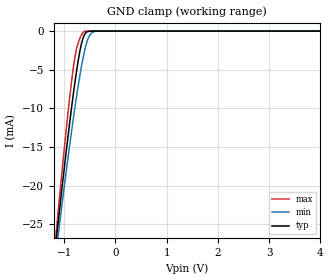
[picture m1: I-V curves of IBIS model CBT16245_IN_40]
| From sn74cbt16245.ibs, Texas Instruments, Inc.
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[Model]   CBT16245_IN_40
Model_type  Input
Vinl = 0.8
Vinh = 2.0
| variable   typ   min   max
C_comp   1.72pF   1.36pF   2.02pF
[Temperature Range]   40   100   -40
| Ambient temperature   25   85   -40
[Voltage range]   4   4   4
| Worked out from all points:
|   GND clamp passes 1 mA (typ) near -0.63 V on its own axis
[GND Clamp]
| CBT16245_IN_40
|   Voltage   I(typ)   I(min)   I(max)
-4V       -223.5mA   -205.4mA   -251.7mA
-1.17V    -28.09mA   -29.44mA   -27.18mA
-1.135V   -25.96mA   -27.52mA   -24.71mA
-1.105V   -24.15mA   -25.9mA    -22.62mA
-940mV    -14.56mA   -17.24mA   -11.62mA
-815mV    -7.933mA   -11.12mA   -4.547mA
-730mV    -4.048mA   -7.314mA   -1.648mA
-665mV    -1.753mA   -4.714mA   -540.1uA
-605mV    -503.4uA   -2.694mA   -38.13uA
-495mV    -19.7uA    -496.6uA   -183.5nA
-350mV    -218.9nA   -15.84uA   -566.2pA
4V        44.9pA     1.797nA    38.62pA
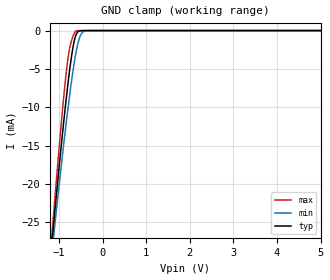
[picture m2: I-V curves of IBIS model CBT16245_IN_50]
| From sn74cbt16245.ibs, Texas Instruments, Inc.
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[Model]   CBT16245_IN_50
Model_type  Input
Vinl = 0.8
Vinh = 2.0
| variable   typ   min   max
C_comp   1.85pF   1.32pF   3.88pF
[Temperature Range]   40   100   -40
| Ambient temperature   25   85   -40
[Voltage range]   5   4.5   5.5
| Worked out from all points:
|   GND clamp passes 1 mA (typ) near -0.63 V on its own axis
[GND Clamp]
| CBT16245_IN_50
|   Voltage   I(typ)   I(min)   I(max)
-5V       -295.8mA   -271mA     -334.4mA
-1.165V   -27.79mA   -29.16mA   -26.83mA
-1.125V   -25.35mA   -26.98mA   -24.01mA
-1.09V    -23.25mA   -25.09mA   -21.58mA
-915mV    -13.17mA   -15.97mA   -10.07mA
-815mV    -7.933mA   -11.12mA   -4.547mA
-725mV    -3.845mA   -7.103mA   -1.541mA
-665mV    -1.753mA   -4.714mA   -540.1uA
-605mV    -503.4uA   -2.694mA   -38.13uA
-490mV    -16.91uA   -448.5uA   -150.3nA
-340mV    -160.5nA   -12.22uA   -381.2pA
5V        55.96pA    1.819nA    44.39pA
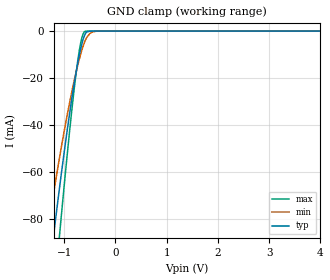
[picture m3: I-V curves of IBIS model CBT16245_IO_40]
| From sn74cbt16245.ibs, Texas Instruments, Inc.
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[Model]   CBT16245_IO_40
Model_type  Terminator
| variable   typ   min   max
C_comp   2.88pF   2.34pF   3.59pF
| C_tri-state   2.88pF   2.34pF   3.59pF
[Temperature Range]   40   100   -40
| Ambient temperature   25   85   -40
[Voltage range]   4   4   4
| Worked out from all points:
|   GND clamp passes 1 mA (typ) near -0.58 V on its own axis
[GND Clamp]
| CBT16245_IO_40
|   Voltage   I(typ)   I(min)   I(max)
-4V       -1.707A    -1.716A    -1.581A
-1.315V   -107.5mA   -84.68mA   -142.9mA
-1.18V    -82.73mA   -65.84mA   -109.1mA
-1.115V   -71.3mA    -57.3mA    -93.3mA
-1.055V   -61.06mA   -49.68mA   -79.08mA
-890mV    -34.81mA   -30.26mA   -42.17mA
-770mV    -18.13mA   -17.93mA   -18.75mA
-680mV    -7.881mA   -10.1mA    -5.457mA
-605mV    -2.054mA   -4.974mA   -284.7uA
-500mV    -47.89uA   -1.099mA   -1.552uA
-365mV    -602.6nA   -40.66uA   -7.164nA
4V        55.92pA    2.053nA    35.56pA
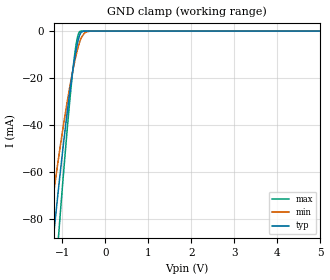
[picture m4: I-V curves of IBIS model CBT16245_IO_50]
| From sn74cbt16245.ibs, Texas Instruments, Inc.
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[Model]   CBT16245_IO_50
Model_type  Terminator
| variable   typ   min   max
C_comp   2.91pF   2.26pF   5.04pF
| C_tri-state   2.91pF   2.26pF   5.04pF
[Temperature Range]   40   100   -40
| Ambient temperature   25   85   -40
[Voltage range]   5   4.5   5.5
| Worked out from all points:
|   GND clamp passes 1 mA (typ) near -0.58 V on its own axis
[GND Clamp]
| CBT16245_IO_50
|   Voltage   I(typ)   I(min)   I(max)
-5V       -2.088A    -2.151A    -1.884A
-1.315V   -107.5mA   -84.68mA   -142.9mA
-1.18V    -82.73mA   -65.84mA   -109.1mA
-1.115V   -71.3mA    -57.3mA    -93.3mA
-1.055V   -61.07mA   -49.68mA   -79.08mA
-890mV    -34.81mA   -30.26mA   -42.17mA
-735mV    -13.84mA   -14.72mA   -12.96mA
-655mV    -5.588mA   -8.223mA   -3.014mA
-580mV    -925.4uA   -3.665mA   -37.68uA
-500mV    -47.89uA   -1.099mA   -1.552uA
-355mV    -438nA     -30.78uA   -4.811nA
5V        71.79pA    2.069nA    45.79pA
